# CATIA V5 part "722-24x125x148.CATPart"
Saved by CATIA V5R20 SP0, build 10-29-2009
Part number: 722-24x125x148
Definition: NONE
Nomenclature: 722-24x125x148
Source: Unknown
Description: 722-24x125x148
Bounding box of the stored display mesh (mm): x -12 to 12, y -12 to 12, z -113 to 35
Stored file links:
  C:\Users\Utente\Desktop\IO LAVORO\3D X SITO CF\X SITO\722\722-24x125x148.CATPart

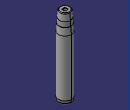
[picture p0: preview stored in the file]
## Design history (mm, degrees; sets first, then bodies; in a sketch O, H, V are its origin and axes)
Body1 "722-24x125x148" (main body)
  Solid1: solid without history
